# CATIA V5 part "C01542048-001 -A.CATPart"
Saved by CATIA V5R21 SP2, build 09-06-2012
Part number: C01542048-001
Revision: ---
Description: PROPRIETARY NOTICE (do not delete / modify)  ***************************************************************************************************  LA SOCIETE EN COMMANDITE  AIRBUS CANADA  ("AIRBUS CANADA")  PAR  L'INTERMEDIAIRE  DE  SES  DIVISIONS  ET/OU  FILIALES  CORPORATIVES,  FOURNIT  LES PRESENTES  INFORMATIONS  AU  GOUVERNEMENT  A  TITRE CONFIDENTIEL. CES  INFORMATIONS ONT UNE TENEUR CONFIDENTIELLE,  AVEC DROITS DE PROPRIETE,  ET NOUS LES CONSIDERONS  EXCLUS  DE   L'APPLICATION  DE  LA LOI SUR L'ACCES A L'INFORMATION  (CANADA),  LES  LOIS  SUR  L'ACCES  A  L'INFORMATION  EUROPEENNES,  LE FREEDOM OF INFORMATION ACT (ETATS-UNIS) ET D'AUTRES LOIS SEMBLABLES. ELLES  PEUVENT  AUSSI  CONSTITUER DES SECRETS INDUSTRIELS DE NOTRE SOCIETE OU DE TIERCES PARTIES. LA DIVULGATION  PUBLIQUE  DE CES  INFORMATIONS NUIRAIT A AIRBUS CANADA OU A DES TIERCES PARTIES.  CES INFORMATIONS PEUVENT EGALEMENT CONTENIR  DES DONNEES QUI SONT CONTROLEE PAR DES LOIS DE CONTROLE DES EXPORTATIONS DU CANADA, L’EUROPE OU LES  ETATS-  UNIS. TOUTE EXPORTATION OU REEXPORTATION DE DONNEES CONTROLEES SANS AUTORISATION EST STRICTEMENT INTERDITE.  TOUTE INTENTION DE LES DIVULGUER EN TOUT OU EN PARTIE DEVRA ETRE SIGNIFIEE A L'AVANCE ET PAR ECRIT AU VICE-  PRESIDENT, SERVICES JURIDIQUES ET CONFORMITE ET SECRETAIRE CORPORATIF D'AIRBUS CANADA.    AIRBUS CANADA LIMITED PARTNERSHIP  ("AIRBUS CANADA"),  BY ITS AFFILIATES AND/OR SUBSIDIARIES, PROVIDES THIS  INFORMATION TO THE GOVERNMENT IN CONFIDENCE. THIS IS PROPRIETARY CONFIDENTIAL INFORMATION WHICH WE CONSIDER  EXCLUDED  FROM  THE  APPLICATION OF THE ACCESS TO INFORMATION ACT (CANADA),  THE FREEDOM OF INFORMATION ACT  (U.S.A.),  THE ACCESS TO INFORMATION LAWS IN EUROPE, AND OTHER SIMILAR LEGISLATION. AND MAY ALSO CONSTITUTE  TRADE SECRETS OF OUR  COMPANY OR THIRD PARTIES.  PUBLIC  RELEASE  OF  THIS INFORMATION  WOULD BE HARMFUL TO  AIRBUS CANADA OR THIRD PARTIES.  THIS  INFORMATION  MAY  ALSO  CONTAIN DATA THAT IS CONTROLLED BY CANADIAN,  EUROPEAN, OR U.S.A. EXPORT CONTROL LAWS. ANY UNAUTHORIZED EXPORT OR RE-EXPORT OF ANY EXPORT CONTROLLED DATA  IS STRICTLY PROHIBITED  ANY INTENTION TO DISCLOSE SUCH INFORMATION,  OR  PART THEREOF,  MUST BE NOTIFIED IN  ADVANCE AND IN WRITING TO THE VICE PRESIDENT, LEGAL AND COMPLIANCE AND CORPORATE SECRETARY OF AIRBUS CANADA.        LES RENSEIGNEMENTS,  LES DONNEES  ET  DESSINS  TECHNIQUES  DIVULGUES  DANS  LES PRESENTES SONT LA PROPRIETE  EXCLUSIVE DE LA SOCIETE EN COMMANDITE AIRBUS CANADA ("AIRBUS CANADA") OU COMPORTENT DES DROITS DE PROPRIETE  APPARTENANT  A  AUTRUI ET NE PEUVENT ETRE DIVULGUES  A  QUICONQUE  NI  UTILISES PAR QUI QUE CE SOIT SANS LE  CONSENTEMENT  ECRIT  D’AIRBUS  CANADA.  LE DETENTEUR DES  PRESENTES  S'ENGAGE, DANS TOUTES CIRCONSTANCES, A  GARDER CONFIDENTIELS LES DONNEES ET DESSINS TECHNIQUES QU'ELLES CONTIENNENT.   CE QUI PRECEDE NE S'APPLIQUE  PAS  AUX PERSONNES  QUI  ONT DES DROITS DE PROPRIETE SUR CES RENSEIGNEMENTS,  DONNEES TECHNIQUES ET DESSINS  DANS LA MESURE OU CES DROITS EXISTENT.    THE INFORMATION,  TECHNICAL DATA  AND  DESIGNS DISCLOSED HEREIN ARE THE EXCLUSIVE PROPERTY OF AIRBUS CANADA  LIMITED PARTNERSHIP  ("AIRBUS CANADA")  OR  CONTAIN PROPRIETARY RIGHTS OF OTHERS  AND ARE NOT TO BE USED OR  DISCLOSED  TO  OTHERS WITHOUT THE WRITTEN CONSENT OF AIRBUS CANADA.  THE RECIPIENT OF THIS DOCUMENT, BY ITS  RETENTION  AND  USE  AGREES TO  HOLD  IN  CONFIDENCE  THE  TECHNICAL DATA AND DESIGNS CONTAINED HEREIN. THE  FOREGOING SHALL NOT APPLY TO PERSONS HAVING PROPRIETARY RIGHTS TO SUCH INFORMATION,  TECHNICAL DATA OR SUCH  DESIGNS TO THE EXTENT THAT SUCH RIGHTS EXIST.    Copyright 2020 Airbus Canada Limited Partnership. All Rights Reserved.  ***********************************
Property "Title": "AXIS, STOP, AFT SVCE DR"
Property "Dataset Type": "DETAIL"
Property "Supplier Name And CAGE Code": "AIRBUS CANADA LIMITED PARTNERSHIP L0J48"
Property "Major Supplier Code": "LP"
Property "3D Only": "Y"
Property "Material Form": "BAR - ROUND"
Property "Finish Code": "T002"
Property "PCCN": "2"
Property "Organization": "DESIGN"
Property "Design Authority Program": "BD-500"
Property "Color Coded": "N/A"
Property "Thickness": 0
Property "Inside Diameter": 0
Property "Outside Diameter": 1.25
Property "Length": 0
Property "Width": 0
Property "Wall": 0
Property "Wire Gauge": "-"
Property "Alloy": "6AL-4V"
Property "Final Condition": "ANL"
Property "Density": "N/A"
Property "Form": "N/A"
Property "Grade/Composition": "N/A"
Property "Material Class": "N/A"
Property "Mesh Cell Size": "N/A"
Property "Standard Spec Die": "N/A"
Property "Type": "N/A"
Property "Style": "N/A"
Property "MFG Process": "MACHINED"
Property "Material Specification Production": "AMS4928"
Property "Material Description Production": "TITANIUM"
Property "Dimensions": "DIMENSIONS ARE IN INCHES"
Property "Roughness": "ALL MACHINED SURFACES 125 Ra MAX"
Property "Eng. Tolerances": "LINEAR .XX= +/-.03; .XXX= +/-.010; ANGULAR= +/-0.5 DEG"
Property "Tool Design Tolerances": "LINEAR .X= +/-.06; .XX= +/-.015; .XXX= +/-.005; .XXXX= +/-.001; ANGULAR= +/-0.5 DEG"
Property "Project": "BA"
Publications: "PartBody", "Extract.1_Datum_A", "Extract.1_Datum_B", "Extract.1_Datum_C"
Material "TI-6AL-4V": density 4428.78 kg/m3, Young's modulus 1.11695e+11 Pa, Poisson ratio 0.31
Bounding box of the stored display mesh (mm): x -168.402 to 0, y -12.695 to 12.695, z -12.695 to 12.695
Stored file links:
  C:\Users\CQQZ006\Desktop\A220钢钛件\舱门\C01542048-001\C01542048-001 -A.CATPart

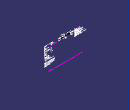
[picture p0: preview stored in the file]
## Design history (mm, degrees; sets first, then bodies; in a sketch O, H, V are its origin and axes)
AxisSystem1 "Absolute Axis System": origin (0, 0, 0), X (1, 0, 0), Y (0, 1, 0), Z (0, 0, 1)
Part_3D_Annotations1 "CATTPSSet"
AxisSystem2 "Copy of Absolute Axis System": origin (0, 0, 0), X (1, 0, 0), Y (0, 1, 0), Z (0, 0, 1)
Set1 "Geometrical Set for 3D Annotations"
  Set2 "No Show Geometry"
    Extract1 "Extract.1_Datum_A": ExtractElem face of Shaft1 from Sketch1.L2
    Extract2 "Extract.1_Datum_B": ExtractElem face of Shaft1 from Sketch1.L5
    Extract3 "Extract.1_Datum_C": ExtractElem face of Shaft1 from Sketch1.L15
Body1 (main body)
  Sketch1 on zx-plane, origin (0, 0, 0), H (-1, 0, 0), V (0, 0, 1)
    line L1 (0, 5.5563) -> (0, 7.62)
    line L2 (43.5864, 7.9223) -> (61.214, 7.9223)
    line L3 (145.6468, 3.175) -> (168.402, 3.175)
    construction line L4 (20.828, -7.9223) -> (34.6372, -7.9223)
    line L5 (168.402, 5.541) -> (153.162, 5.541)
    construction line L6 (148.8263, -5.541) -> (165.2576, -5.541)
    line L7 (144.272, 5.5563) -> (0, 5.5563)
    line L8 (144.272, 5.5563) -> (145.6468, 3.175)
    point P5 (144.272, 5.5563)
    line L9 (168.402, 5.541) -> (168.402, 3.175)
    construction line L10 (152.2657, -3.175) -> (162.0605, -3.175)
    arc A1 centre (153.162, 11.891) radius 6.35 from (148.463, 7.62) to (153.162, 5.541) ccw
    point P10 (148.463, 7.62)
    point P11 (153.162, 5.541)
    line L11 (148.463, 7.62) -> (63.9683, 7.62)
    arc A2 centre (63.9683, 20.32) radius 12.7 from (63.9683, 7.62) to (61.214, 7.9223) cw
    construction line L12 (59.182, 10.4915) -> (59.182, 3.8059)
    point P18 (61.214, 7.9223)
    point P19 (148.463, 7.62)
    line L13 (0, 7.62) -> (41.8084, 7.62)
    construction line L14 (166.37, 8.9132) -> (166.37, -2.7569)
    line L15 (43.3324, 8.1763) -> (43.3324, 12.7)
    line L16 (43.3324, 12.7) -> (42.0624, 12.7)
    arc A3 centre (43.5864, 8.1763) radius 0.254 from (43.3324, 8.1763) to (43.5864, 7.9223) ccw
    line L17 (42.0624, 12.7) -> (42.0624, 7.874)
    arc A4 centre (41.8084, 7.874) radius 0.254 from (41.8084, 7.62) to (42.0624, 7.874) ccw
    construction line L18 (34.8648, -12.7) -> (38.2237, -12.7)
    construction line L19 (0, 0) -> (179.6422, 0)
    construction line L20 (85.2659, -5.5563) -> (94.8005, -5.5563)
    distance L4 L2 = 15.8445
    distance L6 L5 = 11.082
    angle L7 L8 = 120
    distance L7 L2 = 2.366 (reference)
    radius A1 = 6.35
    radius A2 = 12.7
    distance L11 H = 7.62
    distance P18 L12 = 2.032
    distance P18 V = 61.214
    distance L13 H = 7.62
    distance L14 L9 = 2.032
    distance L9 V = 168.402
    distance V L15 = 43.3324
    radius A3 = 0.254
    length L16 = 1.27
    distance P11 L9 = 15.24
    distance P5 L9 = 24.13
    radius A4 = 0.254
    distance L7 L11 = 2.0638 (reference)
    distance L16 L18 = 25.4
    distance L7 L20 = 11.1125
    distance L3 L10 = 6.35
    vertical: L1 V, L9 V, L12 V, L14 V, L15 V, L17 V
    horizontal: L3 H, L4 H, L5 H, L6 H, L7 H, L10 H, L11 H, L13 H, L16 H, L18 H, L19 H, L20 H
    coincidence: O L1, P10 P19
    symmetry: L2 L4 H, L5 L6 H, L16 L18 L19, L20 L7 L19, L3 L10 L19
    tangency: A1 L5, A2 L11, A3 L15, A3 L2, A4 L13, A4 L17
  Shaft1: profile Sketch1, axis Sketch1.H, angle 360
  Body2
  Assemble1: tool Body2
  Body3
  Assemble2: tool Body3
  Chamfer1: length 1.016, angle 45, on edge [face of Shaft1 from Sketch1.L5 | face of Shaft1 from Sketch1.L9]; edge [face of Shaft1 from Sketch1.L1 | face of Shaft1 from Sketch1.L13]
  Body4
  Assemble3: tool Body4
